(* Logix 5000 project; controller Example_PLC vendor 1 type 14 code 77 rev 19.11; software revision 19.01; part 5 of 6 *)
(* tags used below, declared in another part *)
   ENABLE : BOOL;
(* AKD_Set_Parameter, continued *)

ROUTINE Prescan   (* ladder *)
// Prescan
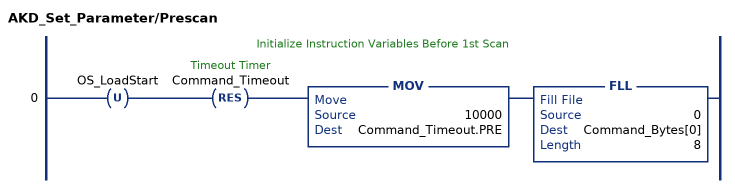
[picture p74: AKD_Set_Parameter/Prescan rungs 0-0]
   // Initialize Instruction Variables Before 1st Scan
   0: OTU(OS_LoadStart)RES(Command_Timeout)MOV(10000,Command_Timeout.PRE)FLL(0,Command_Bytes[0],8);
END_ROUTINE
END_ADD_ON_INSTRUCTION

ADD_ON_INSTRUCTION AKD_Set_Parameter_LINT   (* revision 0.0, ExecutePrescan, ExecuteEnableInFalse *)
// Set 8 byte Drive Parameter
VAR_OUTPUT
   DN : BOOL; {access Read Only, visible}   // Command Successful
   ER : BOOL; {access Read Only, visible}   // Error
END_VAR
VAR_IN_OUT
   Axis : AKD_Axis; {required}
END_VAR
VAR_INPUT
   Parameter_Number : INT; {visible}   // See help (F1) for parameter list.
   Parameter_Value_LSB : DINT; {required}   // Parameter Value
   Parameter_Value_MSB : DINT; {required}
END_VAR
VAR
   Command_Timeout : TIMER := (PRE := 10000);   // Timeout Timer
   Command_Message_Type : SINT;   // Command Message Type
   Command_Axis_Number : SINT;   // Command Axis Number
   Step : SINT;
   Command_Bytes : SINT[8];
   OS_LoadStart : BOOL;
   Temp_Bytes : SINT[2];   // Temporary Bytes to Split into Command Bytes
END_VAR

ROUTINE EnableInFalse   (* ladder *)
// EnableIn_False
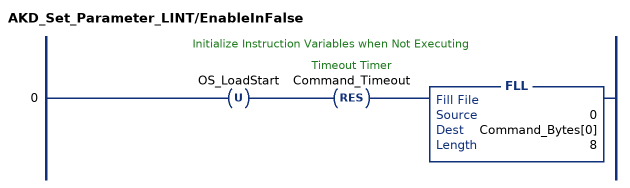
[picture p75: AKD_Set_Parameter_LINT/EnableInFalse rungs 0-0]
   // Initialize Instruction Variables when Not Executing
   0: OTU(OS_LoadStart)RES(Command_Timeout)FLL(0,Command_Bytes[0],8);
END_ROUTINE

ROUTINE Logic   (* ladder *)
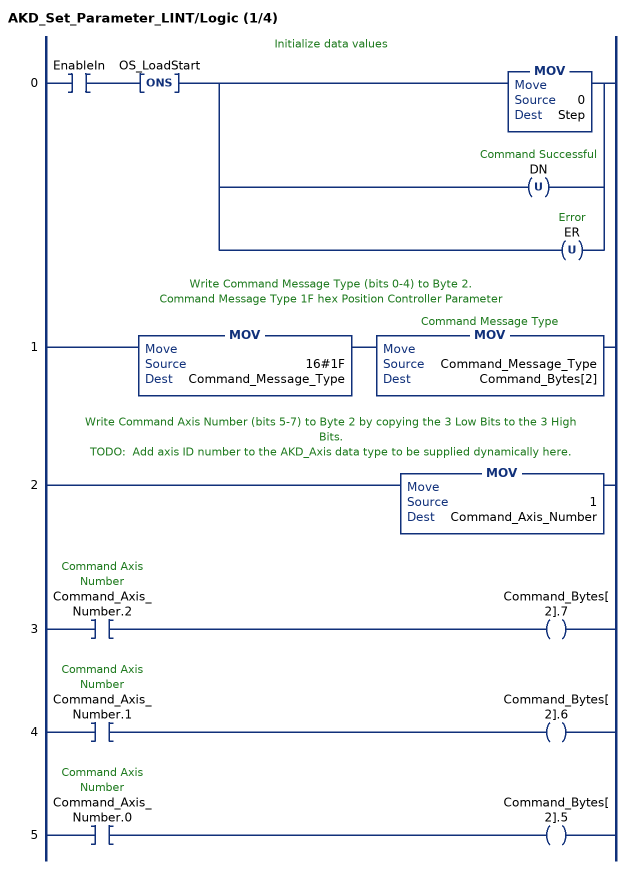
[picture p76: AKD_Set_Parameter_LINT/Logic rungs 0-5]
   // Initialize data values
   0: XIC(EnableIn)ONS(OS_LoadStart)[MOV(0,Step) ,OTU(DN) ,OTU(ER) ];
   // Write Command Message Type (bits 0-4) to Byte 2.
   // Command Message Type 1F hex Position Controller Parameter
   1: MOV(16#1F,Command_Message_Type)MOV(Command_Message_Type,Command_Bytes[2]);
   // Write Command Axis Number (bits 5-7) to Byte 2 by copying the 3 Low Bits to the 3 High Bits.
   // TODO:  Add axis ID number to the AKD_Axis data type to be supplied dynamically here.
   2: MOV(1,Command_Axis_Number);
   3: XIC(Command_Axis_Number.2)OTE(Command_Bytes[2].7);
   4: XIC(Command_Axis_Number.1)OTE(Command_Bytes[2].6);
   5: XIC(Command_Axis_Number.0)OTE(Command_Bytes[2].5);
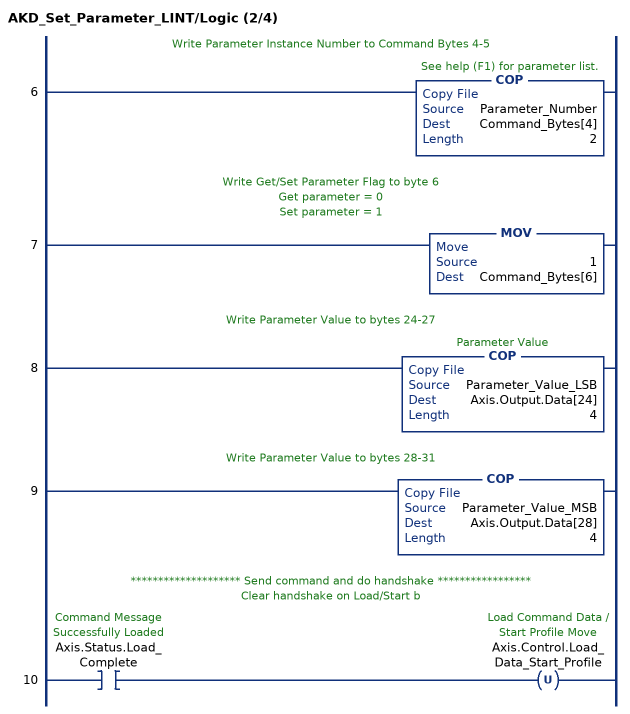
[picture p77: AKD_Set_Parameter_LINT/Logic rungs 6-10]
   // Write Parameter Instance Number to Command Bytes 4-5
   6: COP(Parameter_Number,Command_Bytes[4],2);
   // Write Get/Set Parameter Flag to byte 6
   // Get parameter = 0
   // Set parameter = 1
   7: MOV(1,Command_Bytes[6]);
   // Write Parameter Value to bytes 24-27
   8: COP(Parameter_Value_LSB,Axis.Output.Data[24],4);
   // Write Parameter Value to bytes 28-31
   9: COP(Parameter_Value_MSB,Axis.Output.Data[28],4);
   // ******************** Send command and do handshake *****************
   // Clear handshake on Load/Start b
   10: XIC(Axis.Status.Load_Complete)OTU(Axis.Control.Load_Data_Start_Profile);
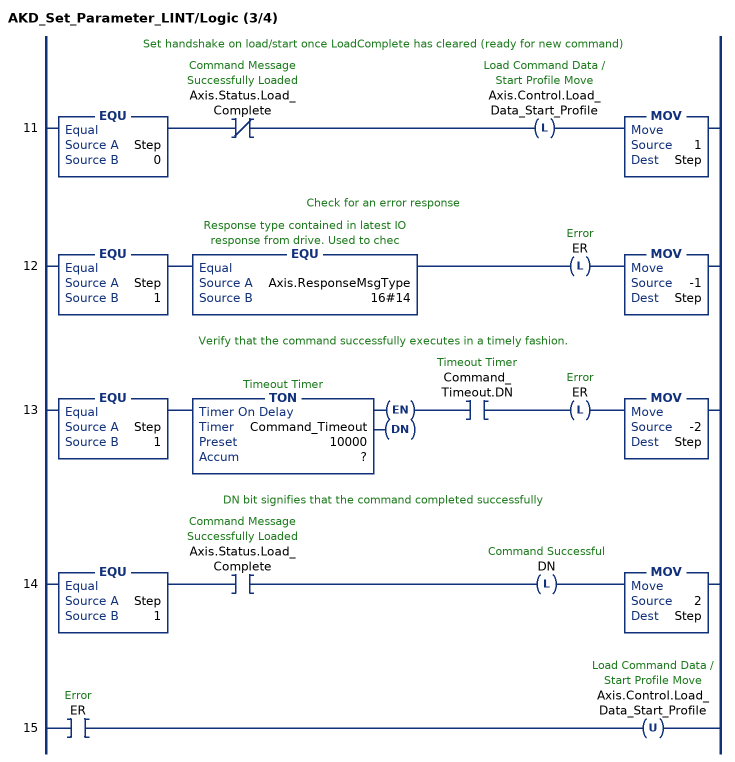
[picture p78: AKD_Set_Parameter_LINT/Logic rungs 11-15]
   // Set handshake on load/start once LoadComplete has cleared (ready for new command)
   11: EQU(Step,0)XIO(Axis.Status.Load_Complete)OTL(Axis.Control.Load_Data_Start_Profile)MOV(1,Step);
   // Check for an error response
   12: EQU(Step,1)EQU(Axis.ResponseMsgType,16#14)OTL(ER)MOV(-1,Step);
   // Verify that the command successfully executes in a timely fashion.
   13: EQU(Step,1)TON(Command_Timeout,?,?)XIC(Command_Timeout.DN)OTL(ER)MOV(-2,Step);
   // DN bit signifies that the command completed successfully
   14: EQU(Step,1)XIC(Axis.Status.Load_Complete)OTL(DN)MOV(2,Step);
   15: XIC(ER)OTU(Axis.Control.Load_Data_Start_Profile);
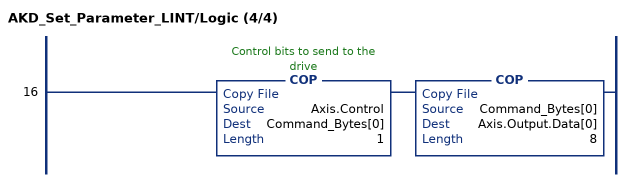
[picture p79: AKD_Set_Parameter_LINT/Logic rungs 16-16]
   16: COP(Axis.Control,Command_Bytes[0],1)COP(Command_Bytes[0],Axis.Output.Data[0],8);
END_ROUTINE

ROUTINE Prescan   (* ladder *)
// Prescan
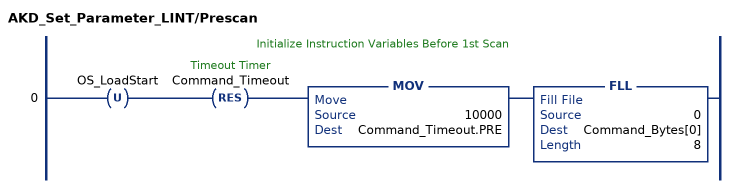
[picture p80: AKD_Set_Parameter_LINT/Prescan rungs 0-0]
   // Initialize Instruction Variables Before 1st Scan
   0: OTU(OS_LoadStart)RES(Command_Timeout)MOV(10000,Command_Timeout.PRE)FLL(0,Command_Bytes[0],8);
END_ROUTINE
END_ADD_ON_INSTRUCTION

ADD_ON_INSTRUCTION AKD_Set_Position   (* revision 2.1, ExecutePrescan, ExecuteEnableInFalse *)
// Set Drive Position
// Revision note:
// Don't error if Command_Timeout preset is 0
VAR_OUTPUT
   DN : BOOL; {access Read Only, visible}   // Command Successful
   ER : BOOL; {access Read Only, visible}   // Error
END_VAR
VAR_IN_OUT
   Axis : AKD_Axis; {required}
END_VAR
VAR_INPUT
   Incremental : BOOL; {visible}   // Position Definition (0=Absolute, 1=Incremental)
   Position : DINT; {required}   // Position Value
END_VAR
VAR_OUTPUT
   PC : BOOL; {access Read Only, visible}   // Process Complete
   IP : BOOL; {access Read Only, visible}   // In Process
END_VAR
VAR
   Response_Bytes : SINT[8];
   OS_LoadStart : BOOL;
   Position_Internal : DINT;   // Scaled Position Value for Drive
   Command_Timeout : TIMER := (PRE := 200);   // Timeout Timer
   Command_Message_Type : SINT;   // Command Message Type
   Command_Axis_Number : SINT;   // Command Axis Number
   Response_Message_Type : SINT;   // Response Message Type
   Response_Axis_Number : SINT;   // Response Axis Number
   Command_Bytes : SINT[8];
   Step : SINT;
END_VAR

ROUTINE EnableInFalse   (* ladder *)
// EnableIn_False
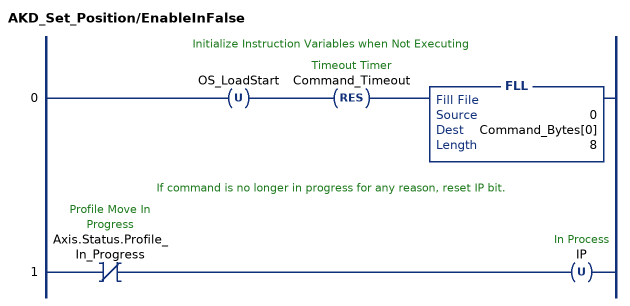
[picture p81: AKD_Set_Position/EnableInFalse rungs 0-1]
   // Initialize Instruction Variables when Not Executing
   0: OTU(OS_LoadStart)RES(Command_Timeout)FLL(0,Command_Bytes[0],8);
   // If command is no longer in progress for any reason, reset IP bit.
   1: XIO(Axis.Status.Profile_In_Progress)OTU(IP);
END_ROUTINE

ROUTINE Logic   (* ladder *)
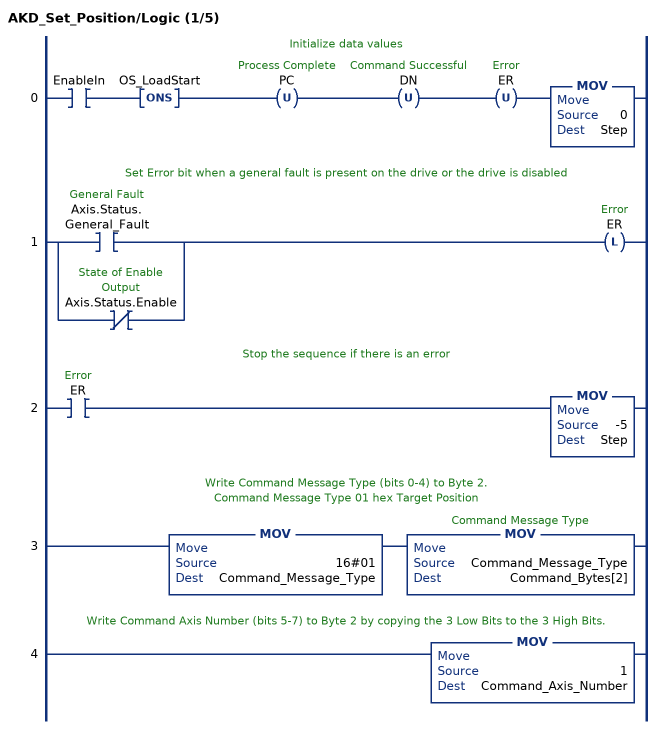
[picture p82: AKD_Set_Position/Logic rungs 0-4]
   // Initialize data values
   0: XIC(EnableIn)ONS(OS_LoadStart)OTU(PC)OTU(DN)OTU(ER)MOV(0,Step);
   // Set Error bit when a general fault is present on the drive or the drive is disabled
   1: [XIC(Axis.Status.General_Fault) ,XIO(Axis.Status.Enable) ]OTL(ER);
   // Stop the sequence if there is an error
   2: XIC(ER)MOV(-5,Step);
   // Write Command Message Type (bits 0-4) to Byte 2.
   // Command Message Type 01 hex Target Position
   3: MOV(16#01,Command_Message_Type)MOV(Command_Message_Type,Command_Bytes[2]);
   // Write Command Axis Number (bits 5-7) to Byte 2 by copying the 3 Low Bits to the 3 High Bits.
   4: MOV(1,Command_Axis_Number);
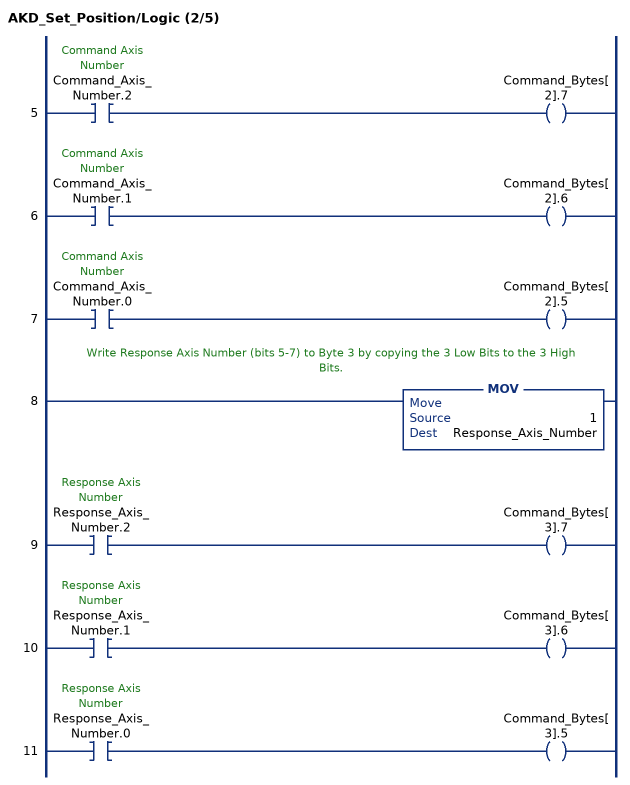
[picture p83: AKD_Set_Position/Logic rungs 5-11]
   5: XIC(Command_Axis_Number.2)OTE(Command_Bytes[2].7);
   6: XIC(Command_Axis_Number.1)OTE(Command_Bytes[2].6);
   7: XIC(Command_Axis_Number.0)OTE(Command_Bytes[2].5);
   // Write Response Axis Number (bits 5-7) to Byte 3 by copying the 3 Low Bits to the 3 High Bits.
   8: MOV(1,Response_Axis_Number);
   9: XIC(Response_Axis_Number.2)OTE(Command_Bytes[3].7);
   10: XIC(Response_Axis_Number.1)OTE(Command_Bytes[3].6);
   11: XIC(Response_Axis_Number.0)OTE(Command_Bytes[3].5);
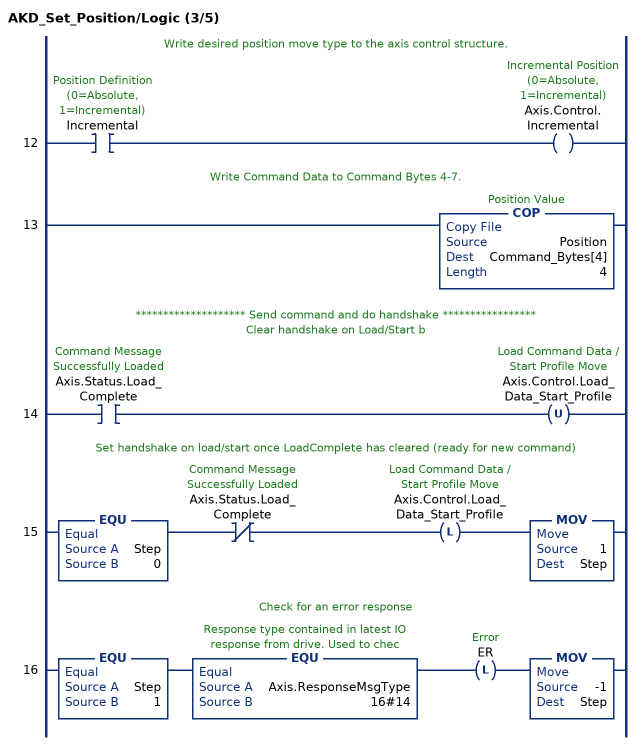
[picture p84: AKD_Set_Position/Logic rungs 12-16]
   // Write desired position move type to the axis control structure.
   12: XIC(Incremental)OTE(Axis.Control.Incremental);
   // Write Command Data to Command Bytes 4-7.
   13: COP(Position,Command_Bytes[4],4);
   // ******************** Send command and do handshake *****************
   // Clear handshake on Load/Start b
   14: XIC(Axis.Status.Load_Complete)OTU(Axis.Control.Load_Data_Start_Profile);
   // Set handshake on load/start once LoadComplete has cleared (ready for new command)
   15: EQU(Step,0)XIO(Axis.Status.Load_Complete)OTL(Axis.Control.Load_Data_Start_Profile)MOV(1,Step);
   // Check for an error response
   16: EQU(Step,1)EQU(Axis.ResponseMsgType,16#14)OTL(ER)MOV(-1,Step);
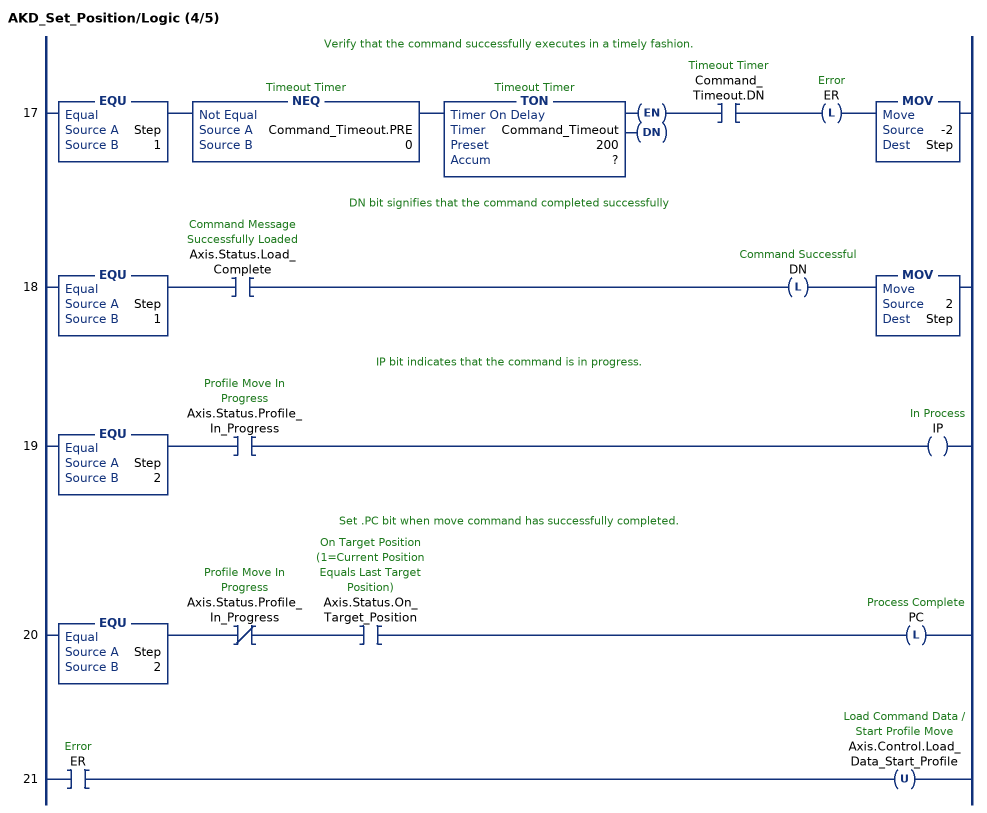
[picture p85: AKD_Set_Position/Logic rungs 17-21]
   // Verify that the command successfully executes in a timely fashion.
   17: EQU(Step,1)NEQ(Command_Timeout.PRE,0)TON(Command_Timeout,?,?)XIC(Command_Timeout.DN)OTL(ER)MOV(-2,Step);
   // DN bit signifies that the command completed successfully
   18: EQU(Step,1)XIC(Axis.Status.Load_Complete)OTL(DN)MOV(2,Step);
   // IP bit indicates that the command is in progress.
   19: EQU(Step,2)XIC(Axis.Status.Profile_In_Progress)OTE(IP);
   // Set .PC bit when move command has successfully completed.
   20: EQU(Step,2)XIO(Axis.Status.Profile_In_Progress)XIC(Axis.Status.On_Target_Position)OTL(PC);
   21: XIC(ER)OTU(Axis.Control.Load_Data_Start_Profile);
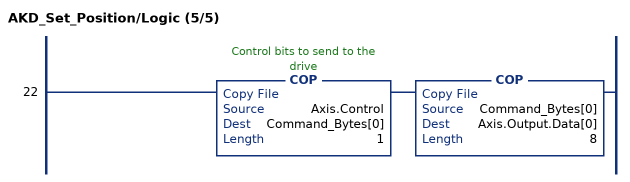
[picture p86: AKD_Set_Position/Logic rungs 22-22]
   22: COP(Axis.Control,Command_Bytes[0],1)COP(Command_Bytes[0],Axis.Output.Data[0],8);
END_ROUTINE

ROUTINE Prescan   (* ladder *)
// Prescan
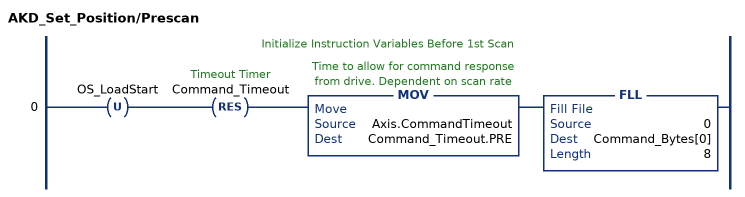
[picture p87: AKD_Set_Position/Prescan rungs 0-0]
   // Initialize Instruction Variables Before 1st Scan
   0: OTU(OS_LoadStart)RES(Command_Timeout)MOV(Axis.CommandTimeout,Command_Timeout.PRE)FLL(0,Command_Bytes[0],8);
END_ROUTINE
END_ADD_ON_INSTRUCTION

ADD_ON_INSTRUCTION AKD_Set_Units   (* revision 2.2, ExecutePrescan, ExecuteEnableInFalse *)
// Set Drive Units for Motion Commands
// Revision note:
// Clean up instruction, especially for error recovery.
VAR_IN_OUT
   Axis : AKD_Axis; {required}
END_VAR
VAR_INPUT
   Units : SINT; {required}   // Drive Units (0=Counts 16 bit)
END_VAR
VAR_OUTPUT
   DN : BOOL; {access Read Only, visible}   // Command Successfully Initiated
   ER : BOOL; {access Read Only, visible}   // Error
END_VAR
VAR
   Set_POSUNIT : AKD_Set_Attribute := (Attribute_Number := 4);
   Set_PROFUNIT : AKD_Set_Attribute := (Attribute_Number := 5);
   Step : SINT;   // Sequence Step Number
   OS_Start_Sequence : BOOL;
   Profile_Ratio : DINT;   // The number of actual feedback counts per second or second2 equal to one velocity or acceleration unit
   Position_Ratio : DINT;   // The number of actual position feedback counts equal to one position unit
   Invalid_Input : BOOL;   // Invalid Units Input
END_VAR

ROUTINE EnableInFalse   (* ladder *)
// EnableIn_False
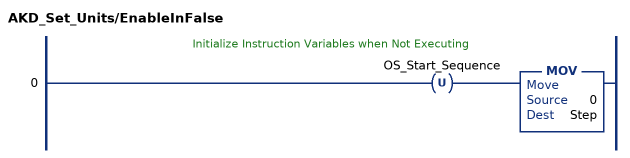
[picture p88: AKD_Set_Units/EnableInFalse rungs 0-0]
   // Initialize Instruction Variables when Not Executing
   0: OTU(OS_Start_Sequence)MOV(0,Step);
END_ROUTINE

ROUTINE Logic   (* ladder *)
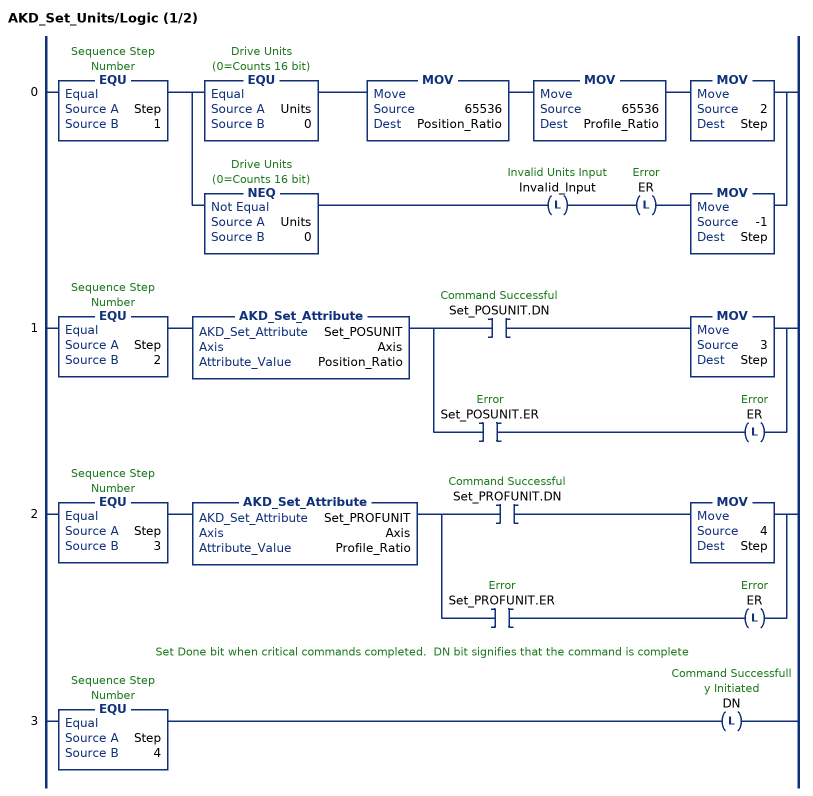
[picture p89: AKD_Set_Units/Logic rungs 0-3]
   0: EQU(Step,1)[EQU(Units,0) MOV(65536,Position_Ratio) MOV(65536,Profile_Ratio) MOV(2,Step) ,NEQ(Units,0) OTL(Invalid_Input) OTL(ER) MOV(-1,Step) ];
   1: EQU(Step,2)AKD_Set_Attribute(Set_POSUNIT,Axis,Position_Ratio)[XIC(Set_POSUNIT.DN) MOV(3,Step) ,XIC(Set_POSUNIT.ER) OTL(ER) ];
   2: EQU(Step,3)AKD_Set_Attribute(Set_PROFUNIT,Axis,Profile_Ratio)[XIC(Set_PROFUNIT.DN) MOV(4,Step) ,XIC(Set_PROFUNIT.ER) OTL(ER) ];
   // Set Done bit when critical commands completed.  DN bit signifies that the command is complete
   3: EQU(Step,4)OTL(DN);
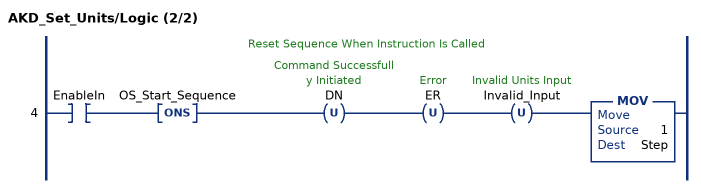
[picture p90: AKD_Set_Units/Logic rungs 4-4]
   // Reset Sequence When Instruction Is Called
   4: XIC(EnableIn)ONS(OS_Start_Sequence)OTU(DN)OTU(ER)OTU(Invalid_Input)MOV(1,Step);
END_ROUTINE

ROUTINE Prescan   (* ladder *)
// Prescan
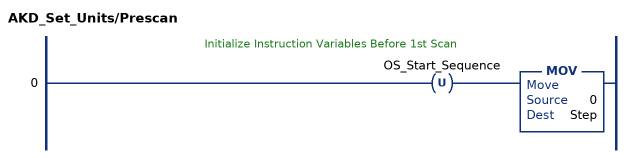
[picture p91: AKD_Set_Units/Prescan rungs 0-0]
   // Initialize Instruction Variables Before 1st Scan
   0: OTU(OS_Start_Sequence)MOV(0,Step);
END_ROUTINE
END_ADD_ON_INSTRUCTION
